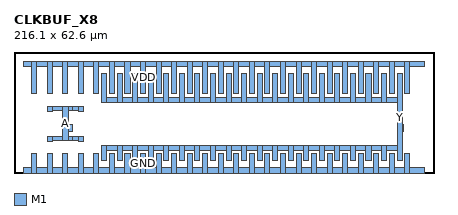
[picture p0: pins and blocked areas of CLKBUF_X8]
MACRO CLKBUF_X8
  CLASS CORE ;
  ORIGIN 0 0 ;
  SIZE 216.100 BY 62.600 ;
  SYMMETRY X Y ;
  SITE TR1um_site ;
  PIN A
    DIRECTION INPUT ;
    USE SIGNAL ;
    PORT
      LAYER M1 ;
        RECT 17.100 16.400 19.700 19.000 ;
      LAYER M1 ;
        RECT 17.100 31.800 19.700 34.400 ;
      LAYER M1 ;
        RECT 19.700 16.700 24.700 18.700 ;
      LAYER M1 ;
        RECT 19.700 32.100 24.700 34.100 ;
      LAYER M1 ;
        RECT 24.700 16.700 28.100 34.100 ;
      LAYER M1 ;
        RECT 28.100 16.700 30.000 18.700 ;
      LAYER M1 ;
        RECT 28.100 21.600 30.000 25.000 ;
      LAYER M1 ;
        RECT 28.100 32.100 30.000 34.100 ;
      LAYER M1 ;
        RECT 30.000 16.700 33.100 18.700 ;
      LAYER M1 ;
        RECT 30.000 32.100 33.100 34.100 ;
      LAYER M1 ;
        RECT 33.100 16.400 35.700 19.000 ;
      LAYER M1 ;
        RECT 33.100 31.800 35.700 34.400 ;
    END
  END A
  PIN Y
    DIRECTION OUTPUT ;
    USE SIGNAL ;
    PORT
      LAYER M1 ;
        RECT 45.100 6.400 47.700 14.400 ;
      LAYER M1 ;
        RECT 45.100 36.400 47.700 51.200 ;
      LAYER M1 ;
        RECT 47.700 11.800 53.100 14.400 ;
      LAYER M1 ;
        RECT 47.700 36.400 53.100 39.000 ;
      LAYER M1 ;
        RECT 53.100 6.400 55.700 14.400 ;
      LAYER M1 ;
        RECT 53.100 36.400 55.700 51.200 ;
      LAYER M1 ;
        RECT 55.700 11.800 61.100 14.400 ;
      LAYER M1 ;
        RECT 55.700 36.400 61.100 39.000 ;
      LAYER M1 ;
        RECT 61.100 6.400 63.700 14.400 ;
      LAYER M1 ;
        RECT 61.100 36.400 63.700 51.200 ;
      LAYER M1 ;
        RECT 63.700 11.800 69.100 14.400 ;
      LAYER M1 ;
        RECT 63.700 36.400 69.100 39.000 ;
      LAYER M1 ;
        RECT 69.100 6.400 71.700 14.400 ;
      LAYER M1 ;
        RECT 69.100 36.400 71.700 51.200 ;
      LAYER M1 ;
        RECT 71.700 11.800 77.100 14.400 ;
      LAYER M1 ;
        RECT 71.700 36.400 77.100 39.000 ;
      LAYER M1 ;
        RECT 77.100 6.400 79.700 14.400 ;
      LAYER M1 ;
        RECT 77.100 36.400 79.700 51.200 ;
      LAYER M1 ;
        RECT 79.700 11.800 85.100 14.400 ;
      LAYER M1 ;
        RECT 79.700 36.400 85.100 39.000 ;
      LAYER M1 ;
        RECT 85.100 6.400 87.700 14.400 ;
      LAYER M1 ;
        RECT 85.100 36.400 87.700 51.200 ;
      LAYER M1 ;
        RECT 87.700 11.800 93.100 14.400 ;
      LAYER M1 ;
        RECT 87.700 36.400 93.100 39.000 ;
      LAYER M1 ;
        RECT 93.100 6.400 95.700 14.400 ;
      LAYER M1 ;
        RECT 93.100 36.400 95.700 51.200 ;
      LAYER M1 ;
        RECT 95.700 11.800 101.100 14.400 ;
      LAYER M1 ;
        RECT 95.700 36.400 101.100 39.000 ;
      LAYER M1 ;
        RECT 101.100 6.400 103.700 14.400 ;
      LAYER M1 ;
        RECT 101.100 36.400 103.700 51.200 ;
      LAYER M1 ;
        RECT 103.700 11.800 109.100 14.400 ;
      LAYER M1 ;
        RECT 103.700 36.400 109.100 39.000 ;
      LAYER M1 ;
        RECT 109.100 6.400 111.700 14.400 ;
      LAYER M1 ;
        RECT 109.100 36.400 111.700 51.200 ;
      LAYER M1 ;
        RECT 111.700 11.800 117.100 14.400 ;
      LAYER M1 ;
        RECT 111.700 36.400 117.100 39.000 ;
      LAYER M1 ;
        RECT 117.100 6.400 119.700 14.400 ;
      LAYER M1 ;
        RECT 117.100 36.400 119.700 51.200 ;
      LAYER M1 ;
        RECT 119.700 11.800 125.100 14.400 ;
      LAYER M1 ;
        RECT 119.700 36.400 125.100 39.000 ;
      LAYER M1 ;
        RECT 125.100 6.400 127.700 14.400 ;
      LAYER M1 ;
        RECT 125.100 36.400 127.700 51.200 ;
      LAYER M1 ;
        RECT 127.700 11.800 133.100 14.400 ;
      LAYER M1 ;
        RECT 127.700 36.400 133.100 39.000 ;
      LAYER M1 ;
        RECT 133.100 6.400 135.700 14.400 ;
      LAYER M1 ;
        RECT 133.100 36.400 135.700 51.200 ;
      LAYER M1 ;
        RECT 135.700 11.800 141.100 14.400 ;
      LAYER M1 ;
        RECT 135.700 36.400 141.100 39.000 ;
      LAYER M1 ;
        RECT 141.100 6.400 143.700 14.400 ;
      LAYER M1 ;
        RECT 141.100 36.400 143.700 51.200 ;
      LAYER M1 ;
        RECT 143.700 11.800 149.100 14.400 ;
      LAYER M1 ;
        RECT 143.700 36.400 149.100 39.000 ;
      LAYER M1 ;
        RECT 149.100 6.400 151.700 14.400 ;
      LAYER M1 ;
        RECT 149.100 36.400 151.700 51.200 ;
      LAYER M1 ;
        RECT 151.700 11.800 157.100 14.400 ;
      LAYER M1 ;
        RECT 151.700 36.400 157.100 39.000 ;
      LAYER M1 ;
        RECT 157.100 6.400 159.700 14.400 ;
      LAYER M1 ;
        RECT 157.100 36.400 159.700 51.200 ;
      LAYER M1 ;
        RECT 159.700 11.800 165.100 14.400 ;
      LAYER M1 ;
        RECT 159.700 36.400 165.100 39.000 ;
      LAYER M1 ;
        RECT 165.100 6.400 167.700 14.400 ;
      LAYER M1 ;
        RECT 165.100 36.400 167.700 51.200 ;
      LAYER M1 ;
        RECT 167.700 11.800 173.100 14.400 ;
      LAYER M1 ;
        RECT 167.700 36.400 173.100 39.000 ;
      LAYER M1 ;
        RECT 173.100 6.400 175.700 14.400 ;
      LAYER M1 ;
        RECT 173.100 36.400 175.700 51.200 ;
      LAYER M1 ;
        RECT 175.700 11.800 181.100 14.400 ;
      LAYER M1 ;
        RECT 175.700 36.400 181.100 39.000 ;
      LAYER M1 ;
        RECT 181.100 6.400 183.700 14.400 ;
      LAYER M1 ;
        RECT 181.100 36.400 183.700 51.200 ;
      LAYER M1 ;
        RECT 183.700 11.800 189.100 14.400 ;
      LAYER M1 ;
        RECT 183.700 36.400 189.100 39.000 ;
      LAYER M1 ;
        RECT 189.100 6.400 191.700 14.400 ;
      LAYER M1 ;
        RECT 189.100 36.400 191.700 51.200 ;
      LAYER M1 ;
        RECT 191.700 11.800 197.100 14.400 ;
      LAYER M1 ;
        RECT 191.700 36.400 197.100 39.000 ;
      LAYER M1 ;
        RECT 197.100 6.400 199.700 51.200 ;
      LAYER M1 ;
        RECT 199.700 21.600 200.500 25.000 ;
    END
  END Y
  PIN VDD
    DIRECTION INOUT ;
    USE POWER ;
    PORT
      LAYER M1 ;
        RECT 5.000 55.000 9.100 57.600 ;
      LAYER M1 ;
        RECT 9.100 41.000 11.700 57.600 ;
      LAYER M1 ;
        RECT 11.700 55.000 17.100 57.600 ;
      LAYER M1 ;
        RECT 17.100 41.000 19.700 57.600 ;
      LAYER M1 ;
        RECT 19.700 55.000 25.100 57.600 ;
      LAYER M1 ;
        RECT 25.100 41.000 27.700 57.600 ;
      LAYER M1 ;
        RECT 27.700 55.000 33.100 57.600 ;
      LAYER M1 ;
        RECT 33.100 41.000 35.700 57.600 ;
      LAYER M1 ;
        RECT 35.700 55.000 41.100 57.600 ;
      LAYER M1 ;
        RECT 41.100 41.000 43.700 57.600 ;
      LAYER M1 ;
        RECT 43.700 55.000 49.100 57.600 ;
      LAYER M1 ;
        RECT 49.100 41.000 51.700 57.600 ;
      LAYER M1 ;
        RECT 51.700 55.000 57.100 57.600 ;
      LAYER M1 ;
        RECT 57.100 41.000 59.700 57.600 ;
      LAYER M1 ;
        RECT 59.700 55.000 65.100 57.600 ;
      LAYER M1 ;
        RECT 65.100 41.000 67.700 57.600 ;
      LAYER M1 ;
        RECT 67.700 55.000 73.100 57.600 ;
      LAYER M1 ;
        RECT 73.100 41.000 75.700 57.600 ;
      LAYER M1 ;
        RECT 75.700 55.000 81.100 57.600 ;
      LAYER M1 ;
        RECT 81.100 41.000 83.700 57.600 ;
      LAYER M1 ;
        RECT 83.700 55.000 89.100 57.600 ;
      LAYER M1 ;
        RECT 89.100 41.000 91.700 57.600 ;
      LAYER M1 ;
        RECT 91.700 55.000 97.100 57.600 ;
      LAYER M1 ;
        RECT 97.100 41.000 99.700 57.600 ;
      LAYER M1 ;
        RECT 99.700 55.000 105.100 57.600 ;
      LAYER M1 ;
        RECT 105.100 41.000 107.700 57.600 ;
      LAYER M1 ;
        RECT 107.700 55.000 113.100 57.600 ;
      LAYER M1 ;
        RECT 113.100 41.000 115.700 57.600 ;
      LAYER M1 ;
        RECT 115.700 55.000 121.100 57.600 ;
      LAYER M1 ;
        RECT 121.100 41.000 123.700 57.600 ;
      LAYER M1 ;
        RECT 123.700 55.000 129.100 57.600 ;
      LAYER M1 ;
        RECT 129.100 41.000 131.700 57.600 ;
      LAYER M1 ;
        RECT 131.700 55.000 137.100 57.600 ;
      LAYER M1 ;
        RECT 137.100 41.000 139.700 57.600 ;
      LAYER M1 ;
        RECT 139.700 55.000 145.100 57.600 ;
      LAYER M1 ;
        RECT 145.100 41.000 147.700 57.600 ;
      LAYER M1 ;
        RECT 147.700 55.000 153.100 57.600 ;
      LAYER M1 ;
        RECT 153.100 41.000 155.700 57.600 ;
      LAYER M1 ;
        RECT 155.700 55.000 161.100 57.600 ;
      LAYER M1 ;
        RECT 161.100 41.000 163.700 57.600 ;
      LAYER M1 ;
        RECT 163.700 55.000 169.100 57.600 ;
      LAYER M1 ;
        RECT 169.100 41.000 171.700 57.600 ;
      LAYER M1 ;
        RECT 171.700 55.000 177.100 57.600 ;
      LAYER M1 ;
        RECT 177.100 41.000 179.700 57.600 ;
      LAYER M1 ;
        RECT 179.700 55.000 185.100 57.600 ;
      LAYER M1 ;
        RECT 185.100 41.000 187.700 57.600 ;
      LAYER M1 ;
        RECT 187.700 55.000 193.100 57.600 ;
      LAYER M1 ;
        RECT 193.100 41.000 195.700 57.600 ;
      LAYER M1 ;
        RECT 195.700 55.000 201.100 57.600 ;
      LAYER M1 ;
        RECT 201.100 41.000 203.700 57.600 ;
      LAYER M1 ;
        RECT 203.700 55.000 211.100 57.600 ;
    END
  END VDD
  PIN GND
    DIRECTION INOUT ;
    USE GROUND ;
    PORT
      LAYER M1 ;
        RECT 5.000 0.000 9.100 2.600 ;
      LAYER M1 ;
        RECT 9.100 0.000 11.700 9.800 ;
      LAYER M1 ;
        RECT 11.700 0.000 17.100 2.600 ;
      LAYER M1 ;
        RECT 17.100 0.000 19.700 9.800 ;
      LAYER M1 ;
        RECT 19.700 0.000 25.100 2.600 ;
      LAYER M1 ;
        RECT 25.100 0.000 27.700 9.800 ;
      LAYER M1 ;
        RECT 27.700 0.000 33.100 2.600 ;
      LAYER M1 ;
        RECT 33.100 0.000 35.700 9.800 ;
      LAYER M1 ;
        RECT 35.700 0.000 41.100 2.600 ;
      LAYER M1 ;
        RECT 41.100 0.000 43.700 9.800 ;
      LAYER M1 ;
        RECT 43.700 0.000 49.100 2.600 ;
      LAYER M1 ;
        RECT 49.100 0.000 51.700 9.800 ;
      LAYER M1 ;
        RECT 51.700 0.000 57.100 2.600 ;
      LAYER M1 ;
        RECT 57.100 0.000 59.700 9.800 ;
      LAYER M1 ;
        RECT 59.700 0.000 65.100 2.600 ;
      LAYER M1 ;
        RECT 65.100 0.000 67.700 9.800 ;
      LAYER M1 ;
        RECT 67.700 0.000 73.100 2.600 ;
      LAYER M1 ;
        RECT 73.100 0.000 75.700 9.800 ;
      LAYER M1 ;
        RECT 75.700 0.000 81.100 2.600 ;
      LAYER M1 ;
        RECT 81.100 0.000 83.700 9.800 ;
      LAYER M1 ;
        RECT 83.700 0.000 89.100 2.600 ;
      LAYER M1 ;
        RECT 89.100 0.000 91.700 9.800 ;
      LAYER M1 ;
        RECT 91.700 0.000 97.100 2.600 ;
      LAYER M1 ;
        RECT 97.100 0.000 99.700 9.800 ;
      LAYER M1 ;
        RECT 99.700 0.000 105.100 2.600 ;
      LAYER M1 ;
        RECT 105.100 0.000 107.700 9.800 ;
      LAYER M1 ;
        RECT 107.700 0.000 113.100 2.600 ;
      LAYER M1 ;
        RECT 113.100 0.000 115.700 9.800 ;
      LAYER M1 ;
        RECT 115.700 0.000 121.100 2.600 ;
      LAYER M1 ;
        RECT 121.100 0.000 123.700 9.800 ;
      LAYER M1 ;
        RECT 123.700 0.000 129.100 2.600 ;
      LAYER M1 ;
        RECT 129.100 0.000 131.700 9.800 ;
      LAYER M1 ;
        RECT 131.700 0.000 137.100 2.600 ;
      LAYER M1 ;
        RECT 137.100 0.000 139.700 9.800 ;
      LAYER M1 ;
        RECT 139.700 0.000 145.100 2.600 ;
      LAYER M1 ;
        RECT 145.100 0.000 147.700 9.800 ;
      LAYER M1 ;
        RECT 147.700 0.000 153.100 2.600 ;
      LAYER M1 ;
        RECT 153.100 0.000 155.700 9.800 ;
      LAYER M1 ;
        RECT 155.700 0.000 161.100 2.600 ;
      LAYER M1 ;
        RECT 161.100 0.000 163.700 9.800 ;
      LAYER M1 ;
        RECT 163.700 0.000 169.100 2.600 ;
      LAYER M1 ;
        RECT 169.100 0.000 171.700 9.800 ;
      LAYER M1 ;
        RECT 171.700 0.000 177.100 2.600 ;
      LAYER M1 ;
        RECT 177.100 0.000 179.700 9.800 ;
      LAYER M1 ;
        RECT 179.700 0.000 185.100 2.600 ;
      LAYER M1 ;
        RECT 185.100 0.000 187.700 9.800 ;
      LAYER M1 ;
        RECT 187.700 0.000 193.100 2.600 ;
      LAYER M1 ;
        RECT 193.100 0.000 195.700 9.800 ;
      LAYER M1 ;
        RECT 195.700 0.000 201.100 2.600 ;
      LAYER M1 ;
        RECT 201.100 0.000 203.700 9.800 ;
      LAYER M1 ;
        RECT 203.700 0.000 211.100 2.600 ;
    END
  END GND
END CLKBUF_X8
